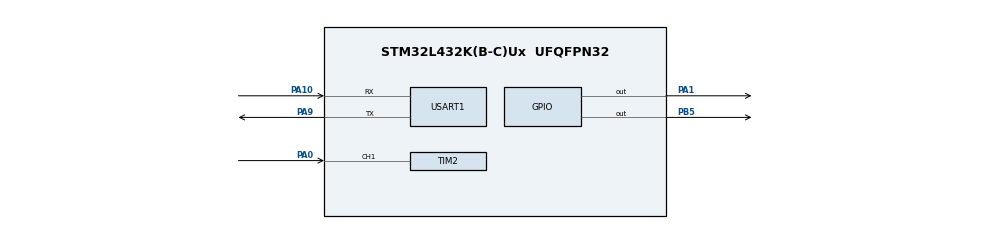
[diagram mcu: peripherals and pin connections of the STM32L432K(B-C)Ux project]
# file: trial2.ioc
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Mcu.Family=STM32L4
RCC.MSI_VALUE=4000000
SH.S_TIM2_CH1.0=TIM2_CH1,Input_Capture1_from_TI1
TIM2.Channel-Input_Capture1_from_TI1=TIM_CHANNEL_1
PA10.Mode=Asynchronous
ProjectManager.StackSize=0x400
USART1.VirtualMode-Asynchronous=VM_ASYNC
PA9.Mode=Asynchronous
TIM2.ICPolarity_CH1=TIM_INPUTCHANNELPOLARITY_BOTHEDGE
ProjectManager.TargetToolchain=MDK-ARM V5
PA9.Signal=USART1_TX
RCC.LSE_VALUE=32768
PA1.Signal=GPIO_Output
RCC.HSE_VALUE=8000000
board=custom
RCC.VCOOutputFreq_Value=32000000
VP_TIM2_VS_ClockSourceINT.Mode=Internal
NVIC.TIM2_IRQn=true\:0\:0\:false\:false\:true\:true\:true
Mcu.Name=STM32L432K(B-C)Ux
PA0.Signal=S_TIM2_CH1
PB5.Signal=GPIO_Output
Mcu.Package=UFQFPN32
PA10.Signal=USART1_RX
ProjectManager.HeapSize=0x200
RCC.HSI_VALUE=16000000
NVIC.PriorityGroup=NVIC_PRIORITYGROUP_4
RCC.HSI48_VALUE=48000000

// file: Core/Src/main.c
/* USER CODE BEGIN Header */
/**
  ******************************************************************************
  * @file           : main.c
  * @brief          : Main program body
  ******************************************************************************
  * @attention
  *
  * <h2><center>&copy; Copyright (c) 2021 STMicroelectronics.
  * All rights reserved.</center></h2>
  *
  * This software component is licensed by ST under BSD 3-Clause license,
  * the "License"; You may not use this file except in compliance with the
  * License. You may obtain a copy of the License at:
  *                        opensource.org/licenses/BSD-3-Clause
  *
  ******************************************************************************
  */
/* USER CODE END Header */
#include "main.h"
#include "taskQueue.h"
#include<string.h>
#include<stdio.h>

/* USER CODE BEGIN PM */
#define Trig_GPIO_Port GPIOA
#define Trig_Pin GPIO_PIN_1
/* USER CODE END PM */

TIM_HandleTypeDef htim2;

UART_HandleTypeDef huart1;

/* USER CODE BEGIN PV */
static const uint16_t MAX_SIZE = 16;
static struct taskQueue main_que;
static struct taskQueue delayed_que;

volatile uint16_t ticks = 0;
volatile char timerFlag = 0;
float buzz=100;
float distance;
uint32_t time=0;
uint32_t return_time;
char pr[100];
uint8_t echo = 0;
uint8_t received=0;
uint32_t riseEdge=0;
uint32_t fallEdge=0;
uint32_t startTick;

const float speedOfSound = 0.0343/2;
/* USER CODE END PV */

void SystemClock_Config(void);
static void MX_GPIO_Init(void);
static void MX_USART1_UART_Init(void);
static void MX_TIM2_Init(void);

/* USER CODE BEGIN PFP */
// Enqueue task in the main queue
static void QueTask(funcPtr f, uint16_t priority)
{
    enqueue(&main_que, f, priority, 0);
}

// dispatch a task and run it if available, otherwise display 'IDLE'

static void dispatch()
{
    // handling the tasks in the delayed Queue first
    decrementDelay(&delayed_que, ticks);
    // enqueue the ready ones to the main Queue
    pushReady(&delayed_que, &main_que);
    // new dispatch --> ticks = 0 for the rest of the tasks
    ticks = 0;
    // dispatch tasks if available
    if (main_que.currentSize > 0)
        dequeue(&main_que).f();
    else
        //printf("IDLE"); // for test purposes
		HAL_UART_Transmit(&huart1 , "IDLE\r\n" , sizeof("IDLE\r\n") , HAL_MAX_DELAY ) ;
}

static void ReRunMe(funcPtr f, uint16_t priority, uint16_t delay)
{
    //enqueue to the main queue if the task is not delayed, otherwise enqueue in the delayed Queue
    if (delay == 0)
        enqueue(&main_que, f, priority, delay);
    else
        enqueue(&delayed_que, f, priority, delay);
}

// initialize Hardware peripherals and Queues
static void init()
{
    // initialize Hardware
    // hardware_init();

    // initialize queues
    que_init(&main_que, MAX_SIZE);
    que_init(&delayed_que, MAX_SIZE);
}

//example tasks
static void f1()
{

		/*
		while((HAL_GetTick() - startTick) < 1000)
		{
			if(echo)
				break;
		}
	*/

		//Print to UART terminal for debugging

}

static void Trig_task()
{
    HAL_UART_Transmit(&huart1, "TRIG\r\n", sizeof("TRIG\r\n"), 100);
		HAL_GPIO_WritePin(Trig_GPIO_Port,Trig_Pin,GPIO_PIN_RESET);
		HAL_Delay(2);
		HAL_GPIO_WritePin(Trig_GPIO_Port, Trig_Pin,GPIO_PIN_SET);
		HAL_Delay(10);
		HAL_GPIO_WritePin(Trig_GPIO_Port, Trig_Pin,GPIO_PIN_RESET);

		HAL_TIM_IC_Start_IT(&htim2, TIM_CHANNEL_1);
		startTick = HAL_GetTick();
	ReRunMe(Trig_task,2,10);
}
static void buzzer()
{
	 HAL_UART_Transmit(&huart1, "buzzer\r\n", sizeof("buzzer\r\n"), 100);
    if (distance < 10 ) {
		HAL_GPIO_TogglePin(GPIOB,GPIO_PIN_5);
		HAL_Delay(buzz);
		}
		else
		HAL_GPIO_WritePin(GPIOB,GPIO_PIN_5 ,GPIO_PIN_RESET );
}
static void evaluate_echo()
{
   HAL_UART_Transmit(&huart1, "echo\r\n", sizeof("echo\r\n"), 100);
		if(echo) {
			echo = 0;
		HAL_TIM_IC_Stop_IT(&htim2, TIM_CHANNEL_1);

		//Calculate distance in cm
		if(fallEdge > riseEdge)
		{
			distance = ((fallEdge - riseEdge) + 0.0f)*0.0343/2;
			buzz=distance * 50;
		}
		else
		{
			distance = 0.0f;
		}
		sprintf(pr, "Distance (cm)  = %.1f\r\n", distance);
		HAL_UART_Transmit(&huart1, (uint8_t *)pr, strlen(pr), 100);
		sprintf(pr, "buzz is %f ", buzz);
		HAL_UART_Transmit(&huart1, (uint8_t *)pr, strlen(pr), 100);
		QueTask(buzzer,2);
		HAL_Delay(100);
		}
		ReRunMe(evaluate_echo,2,2);
}

/* USER CODE END PFP */

int main(void)
{

  /* MCU Configuration--------------------------------------------------------*/

  /* Reset of all peripherals, Initializes the Flash interface and the Systick. */
  HAL_Init();

  /* Configure the system clock */
  SystemClock_Config();

  /* Initialize all configured peripherals */
  MX_GPIO_Init();
  MX_USART1_UART_Init();
  MX_TIM2_Init();
  /* USER CODE BEGIN 2 */
	init();
 QueTask(&Trig_task, 2);
 QueTask(&evaluate_echo, 3);
 //QueTask(&buzzer, 4);
  /* USER CODE END 2 */

  /* Infinite loop */
  while (1)
  {
if (timerFlag)
        {
            dispatch();
            timerFlag = 0;
        }
  }
}

void SystemClock_Config(void)
{
  RCC_OscInitTypeDef RCC_OscInitStruct = {0};
  RCC_ClkInitTypeDef RCC_ClkInitStruct = {0};
  RCC_PeriphCLKInitTypeDef PeriphClkInit = {0};

  /** Configure LSE Drive Capability
  */
  HAL_PWR_EnableBkUpAccess();
  __HAL_RCC_LSEDRIVE_CONFIG(RCC_LSEDRIVE_LOW);
  /** Initializes the RCC Oscillators according to the specified parameters
  * in the RCC_OscInitTypeDef structure.
  */
  RCC_OscInitStruct.OscillatorType = RCC_OSCILLATORTYPE_LSE|RCC_OSCILLATORTYPE_MSI;
  RCC_OscInitStruct.LSEState = RCC_LSE_ON;
  RCC_OscInitStruct.MSIState = RCC_MSI_ON;
  RCC_OscInitStruct.MSICalibrationValue = 0;
  RCC_OscInitStruct.MSIClockRange = RCC_MSIRANGE_6;
  RCC_OscInitStruct.PLL.PLLState = RCC_PLL_ON;
  RCC_OscInitStruct.PLL.PLLSource = RCC_PLLSOURCE_MSI;
  RCC_OscInitStruct.PLL.PLLM = 1;
  RCC_OscInitStruct.PLL.PLLN = 40;
  RCC_OscInitStruct.PLL.PLLP = RCC_PLLP_DIV7;
  RCC_OscInitStruct.PLL.PLLQ = RCC_PLLQ_DIV2;
  RCC_OscInitStruct.PLL.PLLR = RCC_PLLR_DIV2;
  if (HAL_RCC_OscConfig(&RCC_OscInitStruct) != HAL_OK)
  {
    Error_Handler();
  }
  /** Initializes the CPU, AHB and APB buses clocks
  */
  RCC_ClkInitStruct.ClockType = RCC_CLOCKTYPE_HCLK|RCC_CLOCKTYPE_SYSCLK
                              |RCC_CLOCKTYPE_PCLK1|RCC_CLOCKTYPE_PCLK2;
  RCC_ClkInitStruct.SYSCLKSource = RCC_SYSCLKSOURCE_PLLCLK;
  RCC_ClkInitStruct.AHBCLKDivider = RCC_SYSCLK_DIV1;
  RCC_ClkInitStruct.APB1CLKDivider = RCC_HCLK_DIV1;
  RCC_ClkInitStruct.APB2CLKDivider = RCC_HCLK_DIV1;

  if (HAL_RCC_ClockConfig(&RCC_ClkInitStruct, FLASH_LATENCY_4) != HAL_OK)
  {
    Error_Handler();
  }
  PeriphClkInit.PeriphClockSelection = RCC_PERIPHCLK_USART1;
  PeriphClkInit.Usart1ClockSelection = RCC_USART1CLKSOURCE_PCLK2;
  if (HAL_RCCEx_PeriphCLKConfig(&PeriphClkInit) != HAL_OK)
  {
    Error_Handler();
  }
  /** Configure the main internal regulator output voltage
  */
  if (HAL_PWREx_ControlVoltageScaling(PWR_REGULATOR_VOLTAGE_SCALE1) != HAL_OK)
  {
    Error_Handler();
  }
  /** Enable MSI Auto calibration
  */
  HAL_RCCEx_EnableMSIPLLMode();
}

static void MX_TIM2_Init(void)
{

  TIM_ClockConfigTypeDef sClockSourceConfig = {0};
  TIM_MasterConfigTypeDef sMasterConfig = {0};
  TIM_IC_InitTypeDef sConfigIC = {0};

  htim2.Instance = TIM2;
  htim2.Init.Prescaler = 80-1;
  htim2.Init.CounterMode = TIM_COUNTERMODE_UP;
  htim2.Init.Period = 999999;
  htim2.Init.ClockDivision = TIM_CLOCKDIVISION_DIV1;
  htim2.Init.AutoReloadPreload = TIM_AUTORELOAD_PRELOAD_DISABLE;
  if (HAL_TIM_Base_Init(&htim2) != HAL_OK)
  {
    Error_Handler();
  }
  sClockSourceConfig.ClockSource = TIM_CLOCKSOURCE_INTERNAL;
  if (HAL_TIM_ConfigClockSource(&htim2, &sClockSourceConfig) != HAL_OK)
  {
    Error_Handler();
  }
  if (HAL_TIM_IC_Init(&htim2) != HAL_OK)
  {
    Error_Handler();
  }
  sMasterConfig.MasterOutputTrigger = TIM_TRGO_RESET;
  sMasterConfig.MasterSlaveMode = TIM_MASTERSLAVEMODE_DISABLE;
  if (HAL_TIMEx_MasterConfigSynchronization(&htim2, &sMasterConfig) != HAL_OK)
  {
    Error_Handler();
  }
  sConfigIC.ICPolarity = TIM_INPUTCHANNELPOLARITY_BOTHEDGE;
  sConfigIC.ICSelection = TIM_ICSELECTION_DIRECTTI;
  sConfigIC.ICPrescaler = TIM_ICPSC_DIV1;
  sConfigIC.ICFilter = 4;
  if (HAL_TIM_IC_ConfigChannel(&htim2, &sConfigIC, TIM_CHANNEL_1) != HAL_OK)
  {
    Error_Handler();
  }

}

static void MX_USART1_UART_Init(void)
{

  huart1.Instance = USART1;
  huart1.Init.BaudRate = 9600;
  huart1.Init.WordLength = UART_WORDLENGTH_8B;
  huart1.Init.StopBits = UART_STOPBITS_1;
  huart1.Init.Parity = UART_PARITY_NONE;
  huart1.Init.Mode = UART_MODE_TX_RX;
  huart1.Init.HwFlowCtl = UART_HWCONTROL_NONE;
  huart1.Init.OverSampling = UART_OVERSAMPLING_16;
  huart1.Init.OneBitSampling = UART_ONE_BIT_SAMPLE_DISABLE;
  huart1.AdvancedInit.AdvFeatureInit = UART_ADVFEATURE_NO_INIT;
  if (HAL_UART_Init(&huart1) != HAL_OK)
  {
    Error_Handler();
  }

}

static void MX_GPIO_Init(void)
{
  GPIO_InitTypeDef GPIO_InitStruct = {0};

  /* GPIO Ports Clock Enable */
  __HAL_RCC_GPIOC_CLK_ENABLE();
  __HAL_RCC_GPIOA_CLK_ENABLE();
  __HAL_RCC_GPIOB_CLK_ENABLE();

  /*Configure GPIO pin Output Level */
  HAL_GPIO_WritePin(Trig_GPIO_Port, Trig_Pin, GPIO_PIN_RESET);

  /*Configure GPIO pin Output Level */
  HAL_GPIO_WritePin(GPIOB, GPIO_PIN_5, GPIO_PIN_RESET);

  /*Configure GPIO pin : Trig_Pin */
  GPIO_InitStruct.Pin = Trig_Pin;
  GPIO_InitStruct.Mode = GPIO_MODE_OUTPUT_PP;
  GPIO_InitStruct.Pull = GPIO_NOPULL;
  GPIO_InitStruct.Speed = GPIO_SPEED_FREQ_LOW;
  HAL_GPIO_Init(Trig_GPIO_Port, &GPIO_InitStruct);

  /*Configure GPIO pin : PB5 */
  GPIO_InitStruct.Pin = GPIO_PIN_5;
  GPIO_InitStruct.Mode = GPIO_MODE_OUTPUT_PP;
  GPIO_InitStruct.Pull = GPIO_NOPULL;
  GPIO_InitStruct.Speed = GPIO_SPEED_FREQ_LOW;
  HAL_GPIO_Init(GPIOB, &GPIO_InitStruct);

}

/* USER CODE BEGIN 4 */

void HAL_TIM_IC_CaptureCallback(TIM_HandleTypeDef *htim)
{
		if(received == 0) //rising edge
		{
			riseEdge = HAL_TIM_ReadCapturedValue(htim, TIM_CHANNEL_1);
			received = 1;
		}
		else if(received == 1) //falling edge
		{
			fallEdge = HAL_TIM_ReadCapturedValue(htim, TIM_CHANNEL_1);
			received = 0;
			echo = 1;
		}
}

/* USER CODE END 4 */

void Error_Handler(void)
{
  __disable_irq();
  while (1)
  {
  }
}

/************************ (C) COPYRIGHT STMicroelectronics *****END OF FILE****/
